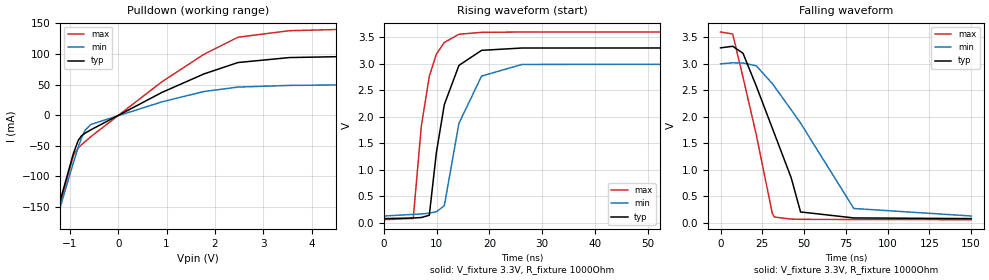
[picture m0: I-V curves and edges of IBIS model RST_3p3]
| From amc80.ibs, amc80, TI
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|   RST model
[Model]  RST_3p3
Model_type   Open_drain
Polarity   Non-Inverting
Vmeas = 1.65
Vref = 1.65
Cref = 15pF
Rref = 50
|   typ   min   max
|   (nom PVT)   (Fast PVT)   (slow PVT)
|   ON state : BUFFER OUTPUT TURNED HIGH
|C_comp   1.331E-12   1.038E-12   1.439E-12
|   OFF state: BUFFER OUTPUT TURNED LOW
C_comp   9.685E-13   8.955E-13   1.043E-12
| Where   nom PVT is  Nominal Process, 3.3V, 27C
|   Fast PVT is Strong Process, 3.6V, -40C
|   Slow PVT is Weak Process, 3.0V, 125C
|C_comp - from L-C Tank method, L = 1nH, peak frequency
[Voltage Range]   3.3   3   3.6
[Temperature Range]   27   125   -40
[Pullup Reference]   3.3   3   3.6
[Pulldown Reference]   0   0   0
[Power Clamp Reference]   3.3   3   3.6
[GND Clamp Reference]   0   0   0
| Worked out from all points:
|   slope of the pulldown table from 0 to 0.495 V, typ, clamps not added: 23.9 ohm
|   falling waveform, V_fixture 3.3V, R_fixture 1000Ohm: 20-80 % time 23ns typ, 36.1ns min, 15.5ns max; typ from 3.3 V to 0.076 V
|   rising waveform, V_fixture 3.3V, R_fixture 1000Ohm: 20-80 % time 3.39ns typ, 4.04ns min, 2.82ns max; typ from 0.076 V to 3.3 V
[Pulldown]
|   Voltage   I(typ)   I(min)   I(max)
-3.3V     -814.3mA   -776mA     -897.8mA
-1.355V   -184.2mA   -192.7mA   -192.2mA
-924.6mV  -62.57mA   -77.64mA   -65.52mA
-824.8mV  -41.33mA   -52.07mA   -53.75mA
-756.1mV  -33.8mA    -37.26mA   -48.57mA
-683.5mV  -29.6mA    -24.88mA   -43.56mA
-564.1mV  -24.16mA   -15.38mA   -35.33mA
902.3mV   36.99mA    21.58mA    54.48mA
1.771V    67.33mA    38.52mA    99.45mA
2.476V    86.03mA    45.8mA     127.5mA
3.539V    94.17mA    48.55mA    138.2mA
6.59V     98.58mA    50.8mA     144.3mA
[Ramp]
R_load = 1000
|   typ   min   max
dV/dt_r   1.93427/3.39136e-009   1.72477/4.03427e-009   2.12651/2.82941e-009
dV/dt_f   1.93427/2.30218e-008   1.72258/3.61648e-008   2.12651/1.55468e-008
[Falling Waveform]
V_fixture = 3.3V
V_fixture_min = 3V
V_fixture_max = 3.6V
R_fixture = 1000Ohm
C_fixture = 0F
|   Time   V(typ)   V(min)   V(max)
0s        3.3V       2.997V     3.6V
7.273ns   3.33V      3.018V     3.562V
13.45ns   3.198V     3.013V     2.746V
21.38ns   2.58V      2.962V     1.661V
30.94ns   1.788V     2.627V     180mV
32.2ns    1.684V     2.573V     106.3mV
42.24ns   850.7mV    2.132V     67.27mV
47.9ns    201.5mV    1.879V     62.01mV
79.76ns   89.09mV    267.1mV    60.07mV
150ns     76.22mV    125.6mV    55.81mV
[Rising Waveform]
V_fixture = 3.3V
V_fixture_min = 3V
V_fixture_max = 3.6V
R_fixture = 1000Ohm
C_fixture = 0F
|   Time   V(typ)   V(min)   V(max)
0s        76.22mV    125.4mV    55.81mV
5.534ns   87.8mV     155.7mV    80.88mV
7.069ns   96.93mV    164.1mV    1.822V
8.582ns   138.8mV    177.5mV    2.763V
9.923ns   1.322V     206mV      3.182V
11.43ns   2.228V     318.5mV    3.402V
14.2ns    2.968V     1.874V     3.557V
18.5ns    3.253V     2.767V     3.593V
26.16ns   3.297V     2.987V     3.599V
150ns     3.3V       3V         3.6V
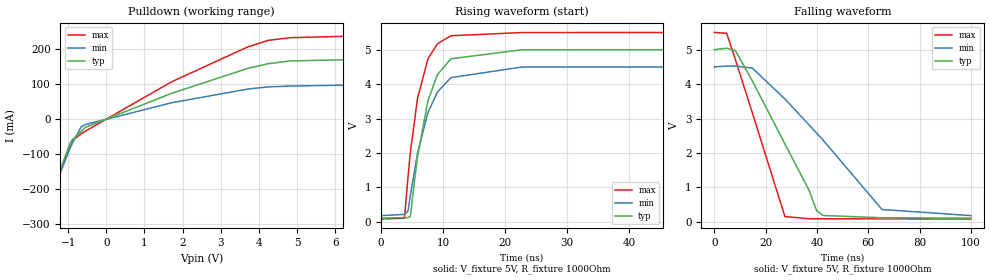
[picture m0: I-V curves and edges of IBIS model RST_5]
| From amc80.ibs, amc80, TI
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[Model]  RST_5
Model_type   Open_drain
Polarity   Non-Inverting
Vmeas = 2.5
Vref = 2.5
Cref = 15pF
Rref = 50
|   typ   min   max
|   (nom PVT)   (Fast PVT)   (slow PVT)
|   ON state : BUFFER OUTPUT TURNED HIGH
|C_comp   1.186E-12   9.865E-13   1.446E-12
|   OFF state: BUFFER OUTPUT TURNED LOW
C_comp   8.832E-13   8.711E-13   9.685E-13
| Where   nom PVT is  Nominal Process, 5.0V, 27C
|   Fast PVT is Strong Process, 5.5V, -40C
|   Slow PVT is Weak Process, 4.5V, 125C
|C_comp - from L-C Tank method, L = 1nH, peak frequency
[Voltage Range]   5   4.5   5.5
[Temperature Range]   27   125   -40
[Pullup Reference]   5   4.5   5.5
[Pulldown Reference]   0   0   0
[Power Clamp Reference]   5   4.5   5.5
[GND Clamp Reference]   0   0   0
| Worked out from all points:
|   slope of the pulldown table from 0 to 0.75 V, typ, clamps not added: 22.5 ohm
|   falling waveform, V_fixture 5V, R_fixture 1000Ohm: 20-80 % time 20.4ns typ, 32ns min, 14ns max; typ from 5 V to 0.112 V
|   rising waveform, V_fixture 5V, R_fixture 1000Ohm: 20-80 % time 3.14ns typ, 3.72ns min, 2.65ns max; typ from 0.111 V to 5 V
[Pulldown]
|   Voltage   I(typ)   I(min)   I(max)
-5V       -1.389A    -1.3A      -1.551A
-1.725V   -300.1mA   -299.8mA   -317.2mA
-961.8mV  -74.29mA   -87.83mA   -76.18mA
-896.1mV  -60.72mA   -71.82mA   -62.84mA
-655.4mV  -35.79mA   -23.02mA   -43.13mA
-548.9mV  -24.76mA   -16.66mA   -35.6mA
1.703V    72.32mA    45.56mA    105.2mA
3.713V    144.3mA    85.05mA    205.8mA
4.242V    157.5mA    91.26mA    224.3mA
4.824V    165.5mA    93.67mA    232mA
8.612V    174.5mA    99.89mA    242.7mA
9.985V    186.3mA    108.6mA    261.6mA
[Ramp]
R_load = 1000
|   typ   min   max
dV/dt_r   2.93312/3.14125e-009   2.58707/3.68027e-009   3.25004/2.65269e-009
dV/dt_f   2.9331/2.04019e-008   2.58984/3.20398e-008   3.25004/1.39605e-008
[Falling Waveform]
V_fixture = 5V
V_fixture_min = 4.5V
V_fixture_max = 5.5V
R_fixture = 1000Ohm
C_fixture = 0F
|   Time   V(typ)   V(min)   V(max)
0s        5V         4.5V       5.5V
4.832ns   5.043V     4.523V     5.476V
8.264ns   4.97V      4.526V     4.705V
14.86ns   4.09V      4.464V     3.163V
27.54ns   2.262V     3.569V     155.4mV
36.97ns   914.5mV    2.812V     93.2mV
39.85ns   330.6mV    2.582V     92.75mV
42.28ns   187.1mV    2.386V     92.37mV
65.37ns   120.7mV    360.3mV    88.73mV
100ns     111.5mV    183.6mV    83.27mV
[Rising Waveform]
V_fixture = 5V
V_fixture_min = 4.5V
V_fixture_max = 5.5V
R_fixture = 1000Ohm
C_fixture = 0F
|   Time   V(typ)   V(min)   V(max)
0s        111.5mV    183.8mV    83.27mV
3.792ns   122.8mV    218.1mV    110mV
4.363ns   124.5mV    317.8mV    1.313V
4.727ns   161.3mV    748.7mV    1.994V
5.88ns    1.874V     1.987V     3.576V
7.572ns   3.522V     3.175V     4.735V
9.111ns   4.279V     3.777V     5.175V
11.28ns   4.736V     4.189V     5.405V
22.74ns   4.998V     4.497V     5.498V
100ns     5V         4.496V     5.5V
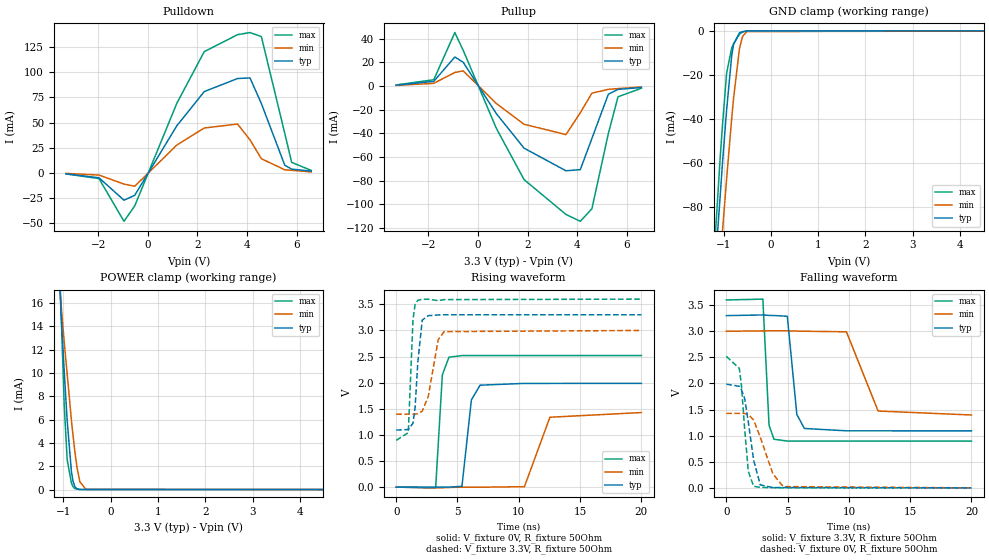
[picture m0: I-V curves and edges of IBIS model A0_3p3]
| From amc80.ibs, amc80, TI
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|   A0 model
[Model]  A0_3p3
Model_type   I/O
Polarity   Non-Inverting
Enable   Active-Low
Vinl = 0.8
Vinh = 2
Vmeas = 1.65
Vref = 1.65
Cref = 15pF
Rref = 50
|   typ   min   max
|   (nom PVT)   (Fast PVT)   (slow PVT)
|   BUFFER as INPUT
|C_comp   1.799E-12   1.507E-12   2.061E-12
|   BUFFER OUTPUT TURNED HIGH
|C_comp   1.730E-12   1.615E-12   1.787E-12
|   BUFFER OUTPUT TURNED LOW
C_comp   1.652E-12   1.439E-12   1.779E-12
| Where   nom PVT is  Nominal Process, 3.3V, 27C
|   Fast PVT is Strong Process, 3.6V, -40C
|   Slow PVT is Weak Process, 3.0V, 125C
|C_comp - from L-C Tank method, L = 1nH, peak frequency
[Voltage Range]   3.3   3   3.6
[Temperature Range]   27   125   -40
[Pullup Reference]   3.3   3   3.6
[Pulldown Reference]   0   0   0
[Power Clamp Reference]   3.3   3   3.6
[GND Clamp Reference]   0   0   0
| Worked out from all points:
|   slope of the pulldown table from 0 to 0.495 V, typ, clamps not added: 23.8 ohm
|   slope of the pullup table from 0 to 0.495 V, typ, clamps not added: 30.7 ohm
|   GND clamp passes 1 mA (typ) near -0.67 V on its own axis
|   POWER clamp passes 1 mA (typ) near -0.81 V on its own axis
|   falling waveform, V_fixture 3.3V, R_fixture 50Ohm: 20-80 % time 488ps typ, 1.12ns min, 294ps max; typ from 3.3 V to 1.09 V
|   rising waveform, V_fixture 0V, R_fixture 50Ohm: 20-80 % time 475ps typ, 958ps min, 306ps max; typ from 0 V to 1.99 V
|   rising waveform, V_fixture 3.3V, R_fixture 50Ohm: 20-80 % time 349ps typ, 693ps min, 243ps max; typ from 1.09 V to 3.3 V
|   falling waveform, V_fixture 0V, R_fixture 50Ohm: 20-80 % time 735ps typ, 1.23ns min, 496ps max; typ from 1.99 V to 0 V
[Pulldown]
|   Voltage   I(typ)   I(min)   I(max)
-3.3V     -1.175mA   -709.3uA   -1.236mA
-1.972V   -5.093mA   -2.383mA   -5.88mA
-963.1mV  -27.42mA   -11.33mA   -48.43mA
-529.5mV  -22.47mA   -13.5mA    -33.01mA
1.168V    46.74mA    27.55mA    69.14mA
2.274V    80.8mA     44.52mA    120.6mA
3.617V    93.81mA    48.47mA    137.5mA
4.119V    94.43mA    32.76mA    139.6mA
4.578V    68.89mA    13.93mA    135.6mA
5.521V    7.533mA    2.891mA    39.29mA
5.8V      3.545mA    2.339mA    10.26mA
6.59V     1.583mA    773.1uA    2.292mA
[GND Clamp]
|   Voltage   I(typ)   I(min)   I(max)
-3.3V     -808.9mA   -769.8mA   -893.6mA
-1.223V   -121.5mA   -147.5mA   -109.9mA
-1.171V   -104.9mA   -132.4mA   -91.88mA
-1.071V   -74.76mA   -104.1mA   -57.53mA
-1.016V   -58.11mA   -89.07mA   -41.04mA
-934.7mV  -35.86mA   -67.02mA   -19.19mA
-827.5mV  -11.31mA   -39.73mA   -7.752mA
-787mV    -6.029mA   -30.41mA   -5.902mA
-662.1mV  -884uA     -7.82mA    -1.506mA
-597.2mV  -409.2uA   -2.526mA   -463.9uA
-507.2mV  -88.16uA   -343.9uA   -46.63uA
6.59V     0A         0A         0A
[Pullup]
|   Voltage   I(typ)   I(min)   I(max)
-3.3V     838.5uA    589uA      957.1uA
-1.785V   3.995mA    2.329mA    5.396mA
-934.7mV  24.58mA    11.54mA    45.22mA
-597.2mV  20.15mA    12.87mA    30.21mA
743mV     -23.36mA   -14.78mA   -35.82mA
1.857V    -52.4mA    -32.24mA   -78.95mA
3.547V    -71.52mA   -40.97mA   -108.4mA
4.127V    -70.56mA   -22.5mA    -114.2mA
4.595V    -44.2mA    -5.965mA   -103.6mA
5.259V    -6.805mA   -2.724mA   -39.96mA
5.649V    -2.762mA   -2.117mA   -8.998mA
6.59V     -1.19mA    -650.2uA   -1.826mA
[POWER Clamp]
|   Voltage   I(typ)   I(min)   I(max)
-3.3V     261.6mA    182.4mA    376.9mA
-1.077V   17.83mA    17.41mA    19mA
-1.04V    14.51mA    15.55mA    14.53mA
-980.9mV  10.21mA    12.68mA    7.284mA
-917.7mV  5.906mA    9.9mA      2.557mA
-827.5mV  1.525mA    5.931mA    553.1uA
-794.7mV  720.3uA    4.675mA    256.2uA
-754.5mV  244.2uA    3.248mA    80.4uA
-709.6mV  76.81uA    1.892mA    48.28uA
-648.9mV  11.09uA    666.7uA    4.808uA
-522mV    8.862uA    26.29uA    2.204uA
6.59V     0A         0A         0A
[Ramp]
R_load = 50
|   typ   min   max
dV/dt_r   1.19193/4.69354e-010   0.85652/9.52893e-010   1.51191/3.05784e-010
dV/dt_f   1.32484/4.84931e-010  0.962182/1.11589e-009   1.62278/2.91861e-010
[Falling Waveform]
V_fixture = 3.3V
V_fixture_min = 3V
V_fixture_max = 3.6V
R_fixture = 50Ohm
C_fixture = 0F
|   Time   V(typ)   V(min)   V(max)
0s        3.3V       3V         3.6V
2.979ns   3.313V     3.008V     3.616V
3.485ns   3.304V     3.009V     1.2V
3.888ns   3.302V     3.01V      931.2mV
4.974ns   3.288V     3.009V     897.2mV
5.752ns   1.407V     3.004V     896mV
6.365ns   1.138V     3.001V     896mV
9.798ns   1.093V     2.99V      895.8mV
12.38ns   1.093V     1.472V     895.7mV
20ns      1.092V     1.396V     895.4mV
[Rising Waveform]
V_fixture = 0V
V_fixture_min = 0V
V_fixture_max = 0V
R_fixture = 50Ohm
C_fixture = 0F
|   Time   V(typ)   V(min)   V(max)
0s        344.5nV    875.3nV    199.8nV
3.219ns   -586.7uV   -14.33mV   -13.52mV
3.764ns   -283.9uV   -12.17mV   2.15V
4.305ns   17.03uV    -6.27mV    2.488V
5.364ns   15.35mV    -937.8uV   2.519V
6.134ns   1.671V     -1.568mV   2.519V
6.842ns   1.952V     -2.148mV   2.519V
10.46ns   1.986V     8.086mV    2.519V
12.54ns   1.986V     1.338V     2.52V
20ns      1.987V     1.428V     2.52V
[Rising Waveform]
V_fixture = 3.3V
V_fixture_min = 3V
V_fixture_max = 3.6V
R_fixture = 50Ohm
C_fixture = 0F
|   Time   V(typ)   V(min)   V(max)
0s        1.092V     1.396V     895.4mV
984.8ps   1.102V     1.398V     1.043V
1.373ns   1.226V     1.399V     3.22V
1.541ns   1.525V     1.399V     3.496V
1.761ns   2.386V     1.405V     3.578V
2.123ns   3.199V     1.454V     3.596V
2.618ns   3.283V     1.738V     3.599V
3.424ns   3.297V     2.818V     3.571V
3.906ns   3.3V       2.978V     3.591V
20ns      3.3V       3V         3.6V
[Falling Waveform]
|Gnd
V_fixture = 0V
V_fixture_min = 0V
V_fixture_max = 0V
R_fixture = 50Ohm
C_fixture = 0F
|   Time   V(typ)   V(min)   V(max)
0s        1.987V     1.428V     2.52V
1.06ns    1.946V     1.427V     2.288V
1.228ns   1.885V     1.427V     1.975V
1.498ns   1.708V     1.426V     1.12V
1.793ns   1.261V     1.406V     316.1mV
2.23ns    529.1mV    1.299V     28.41mV
2.77ns    56.42mV    968.2mV    10.17mV
3.796ns   4.617mV    269.2mV    3.856mV
4.634ns   6.957mV    24.82mV    485.3uV
20ns      344.5nV    874.9nV    199.9nV
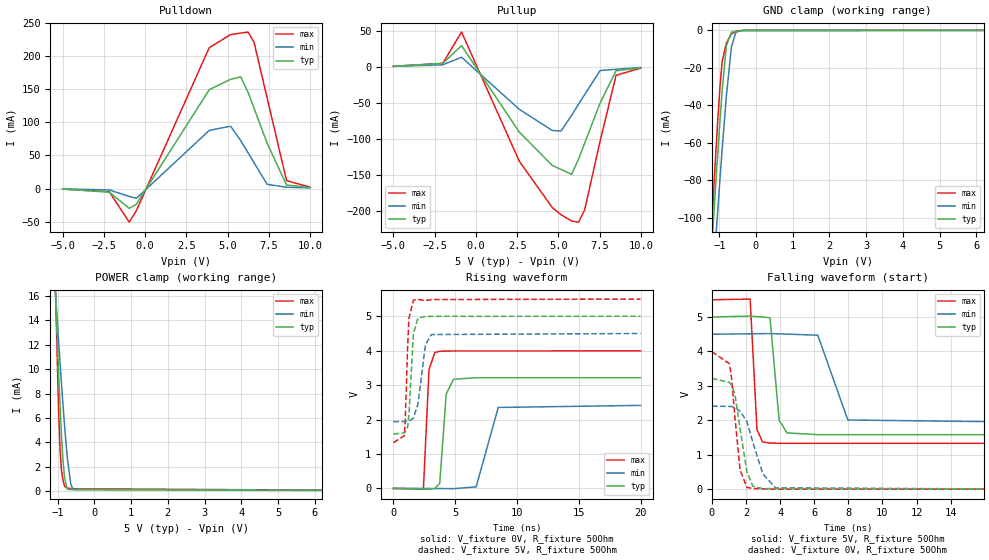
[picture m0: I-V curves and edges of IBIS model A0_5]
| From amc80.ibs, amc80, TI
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[Model]  A0_5
Model_type   I/O
Polarity   Non-Inverting
Enable   Active-Low
Vinl = 0.8
Vinh = 2
Vmeas = 2.5
Vref = 2.5
Cref = 15pF
Rref = 50
|   typ   min   max
|   (nom PVT)   (Fast PVT)   (slow PVT)
|   BUFFER as INPUT
|C_comp   1.730E-12   1.432E-12   1.862E-12
|   BUFFER OUTPUT TURNED HIGH
|C_comp   1.466E-12   1.459E-12   1.614E-12
|   BUFFER OUTPUT TURNED LOW
C_comp   1.486E-12   1.374E-12   1.652E-12
| Where   nom PVT is  Nominal Process, 5.0V, 27C
|   Fast PVT is Strong Process, 5.5V, -40C
|   Slow PVT is Weak Process, 4.5V, 125C
|C_comp - from L-C Tank method, L = 1nH, peak frequency
[Voltage Range]   5   4.5   5.5
[Temperature Range]   27   125   -40
[Pullup Reference]   5   4.5   5.5
[Pulldown Reference]   0   0   0
[Power Clamp Reference]   5   4.5   5.5
[GND Clamp Reference]   0   0   0
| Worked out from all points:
|   slope of the pulldown table from 0 to 0.75 V, typ, clamps not added: 22.6 ohm
|   slope of the pullup table from 0 to 0.75 V, typ, clamps not added: 26.9 ohm
|   GND clamp passes 1 mA (typ) near -0.67 V on its own axis
|   POWER clamp passes 1 mA (typ) near -0.81 V on its own axis
|   falling waveform, V_fixture 5V, R_fixture 50Ohm: 20-80 % time 325ps typ, 640ps min, 226ps max; typ from 5 V to 1.58 V
|   rising waveform, V_fixture 0V, R_fixture 50Ohm: 20-80 % time 345ps typ, 610ps min, 250ps max; typ from 0 V to 3.22 V
|   rising waveform, V_fixture 5V, R_fixture 50Ohm: 20-80 % time 302ps typ, 517ps min, 238ps max; typ from 1.58 V to 5 V
|   falling waveform, V_fixture 0V, R_fixture 50Ohm: 20-80 % time 574ps typ, 876ps min, 430ps max; typ from 3.22 V to 0 V
[Pulldown]
|   Voltage   I(typ)   I(min)   I(max)
-5V       -736.2uA   -519.2uA   -724.3uA
-2.168V   -5.525mA   -2.14mA    -4.899mA
-962.6mV  -29.96mA   -11.89mA   -50.83mA
-530.9mV  -23.62mA   -14.8mA    -33.6mA
3.89V     149.3mA    87.81mA    212.8mA
5.183V    165mA      94.18mA    232.5mA
5.803V    168.6mA    72.24mA    234.8mA
6.248V    145.1mA    53.83mA    236.3mA
6.607V    121.3mA    39.03mA    220.9mA
7.399V    68.57mA    6.298mA    136.9mA
8.578V    5.282mA    2.007mA    11.93mA
9.985V    1.703mA    965.1uA    2.2mA
[GND Clamp]
|   Voltage   I(typ)   I(min)   I(max)
-5V       -1.381A    -1.29A     -1.545A
-1.241V   -127.1mA   -152.1mA   -116.4mA
-1.137V   -94.9mA    -123.2mA   -79.87mA
-1.078V   -76.44mA   -106.5mA   -60.04mA
-1.048V   -67.82mA   -98.25mA   -50.14mA
-980.7mV  -48.24mA   -79.41mA   -30.14mA
-919.9mV  -31.94mA   -63.22mA   -16.41mA
-807mV    -8.294mA   -35.16mA   -6.834mA
-669.1mV  -994uA     -8.907mA   -1.932mA
-545.5mV  -705.3uA   -853.3uA   -451.4uA
-347.5mV  -243.1uA   -4.497uA   -2.357uA
9.985V    0A         0A         0A
[Pullup]
|   Voltage   I(typ)   I(min)   I(max)
-5V       581.8uA    454.9uA    619.1uA
-2.011V   4.527mA    2.646mA    4.591mA
-871.6mV  29.21mA    13.18mA    48.03mA
2.633V    -90.79mA   -59.17mA   -131.2mA
4.633V    -137mA     -88.46mA   -195.5mA
5.163V    -142.6mA   -89.26mA   -205.4mA
5.803V    -149.4mA   -67.45mA   -214.1mA
6.222V    -128.2mA   -52.09mA   -215.7mA
6.597V    -105.9mA   -38.63mA   -198.4mA
7.532V    -50.27mA   -5.259mA   -103.2mA
8.499V    -5.545mA   -3.593mA   -11.86mA
9.985V    -1.656mA   -1.033mA   -2.065mA
[POWER Clamp]
|   Voltage   I(typ)   I(min)   I(max)
-5V       454mA      315.5mA    657.3mA
-1.073V   17.48mA    17.05mA    18.43mA
-1.06V    16.37mA    16.42mA    16.68mA
-971.8mV  9.471mA    12.23mA    6.393mA
-930.2mV  6.767mA    10.35mA    3.206mA
-895.4mV  4.52mA     8.844mA    1.707mA
-854.1mV  2.505mA    7.055mA    876uA
-807mV    970uA      5.168mA    374.3uA
-734.9mV  138.3uA    2.688mA    227.1uA
-641.5mV  112uA      570.9uA    197.3uA
-582.8mV  95.49uA    137.3uA    178.6uA
9.985V    0A         0A         0A
[Ramp]
R_load = 50
|   typ   min   max
dV/dt_r   1.92936/3.43663e-010   1.44734/6.03922e-010   2.39556/2.48588e-010
dV/dt_f   2.05119/3.22273e-010   1.53749/6.3371e-010   2.50192/2.25003e-010
[Falling Waveform]
V_fixture = 5V
V_fixture_min = 4.5V
V_fixture_max = 5.5V
R_fixture = 50Ohm
C_fixture = 0F
|   Time   V(typ)   V(min)   V(max)
0s        5V         4.5V       5.5V
2.242ns   5.027V     4.512V     5.521V
2.643ns   5.01V      4.514V     1.733V
2.963ns   5.004V     4.516V     1.375V
3.406ns   4.976V     4.519V     1.34V
3.943ns   2.002V     4.51V      1.332V
4.407ns   1.634V     4.503V     1.331V
6.21ns    1.583V     4.471V     1.331V
7.971ns   1.582V     2.009V     1.331V
20ns      1.581V     1.938V     1.33V
[Rising Waveform]
V_fixture = 0V
V_fixture_min = 0V
V_fixture_max = 0V
R_fixture = 50Ohm
C_fixture = 0F
|   Time   V(typ)   V(min)   V(max)
0s        329.3nV    663.4nV    197.7nV
2.426ns   -1.697mV   -21.39mV   -9.064mV
2.878ns   -584.1uV   -16.15mV   3.449V
3.344ns   -5.055mV   -4.723mV   3.947V
3.746ns   148.6mV    -2.821mV   3.983V
4.271ns   2.745V     -4.747mV   3.991V
4.861ns   3.169V     -6.908mV   3.992V
6.692ns   3.215V     45.38mV    3.992V
8.481ns   3.215V     2.352V     3.992V
20ns      3.216V     2.412V     3.993V
[Rising Waveform]
V_fixture = 5V
V_fixture_min = 4.5V
V_fixture_max = 5.5V
R_fixture = 50Ohm
C_fixture = 0F
|   Time   V(typ)   V(min)   V(max)
0s        1.581V     1.938V     1.33V
881ps     1.612V     1.947V     1.533V
954.5ps   1.639V     1.947V     1.973V
1.149ns   1.787V     1.949V     4.134V
1.251ns   2.127V     1.95V      4.935V
1.613ns   4.477V     2.039V     5.469V
1.984ns   4.95V      2.451V     5.49V
2.594ns   4.995V     4.181V     5.457V
3.075ns   4.999V     4.47V      5.486V
20ns      5V         4.5V       5.5V
[Falling Waveform]
|Gnd
V_fixture = 0V
V_fixture_min = 0V
V_fixture_max = 0V
R_fixture = 50Ohm
C_fixture = 0F
|   Time   V(typ)   V(min)   V(max)
0s        3.216V     2.412V     3.993V
1.027ns   3.1V       2.402V     3.646V
1.158ns   3.012V     2.401V     3.212V
1.343ns   2.775V     2.37V      2.128V
1.65ns    1.762V     2.267V     565.8mV
2.053ns   503.3mV    1.963V     48.75mV
2.4ns     89.2mV     1.361V     21.97mV
2.986ns   12.34mV    443.8mV    6.692mV
3.729ns   21.69mV    36.2mV     709.7uV
20ns      329.4nV    663.5nV    197.8nV
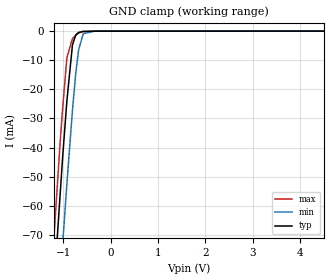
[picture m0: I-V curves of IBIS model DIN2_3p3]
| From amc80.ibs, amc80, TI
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|   DIN2 model
[Model]  DIN2_3p3
Model_type   Input
Vinl = 0.8
Vinh = 2.0
|   typ   min   max
|   (nom PVT)   (Fast PVT)   (slow PVT)
C_comp   5.835E-13   5.676E-13   6.224E-13
| Where   nom PVT is  Nominal Process, 3.3V, 27C
|   Fast PVT is Strong Process, 3.6V, -40C
|   Slow PVT is Weak Process, 3.0V, 125C
|C_comp - from L-C Tank method, L = 1nH, peak frequency
| Where   nom PVT is  Nominal Process, 3.3V, 27C
|   Fast PVT is Strong Process, 3.6V, -40C
|   Slow PVT is Weak Process, 3.0V, 125C
|C_comp - from L-C Tank method, L = 1nH, peak frequency
[Voltage Range]   3.3   3   3.6
[Temperature Range]   27   125   -40
[Power Clamp Reference]   3.3   3   3.6
[GND Clamp Reference]   0   0   0
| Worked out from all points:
|   GND clamp passes 1 mA (typ) near -0.72 V on its own axis
[GND Clamp]
|   Voltage   I(typ)   I(min)   I(max)
-3.3V     -646.6mA   -664.3mA   -639.2mA
-1.233V   -97.24mA   -127mA     -79.71mA
-1.171V   -81.48mA   -111.4mA   -64.21mA
-1.064V   -55.52mA   -85.13mA   -37.57mA
-1.014V   -43.35mA   -73.27mA   -26.64mA
-924.4mV  -23.98mA   -52.53mA   -9.169mA
-806.3mV  -4.748mA   -27.19mA   -2.534mA
-736.8mV  -1.299mA   -14.5mA    -1.496mA
-675.7mV  -477.6uA   -6.375mA   -602.2uA
-578.1mV  -79.57uA   -895.2uA   -247.7uA
-330.4mV  -33.16uA   -1.944uA   -7.412uA
6.59V     0A         0A         0A
[POWER Clamp]
|   SCR cell for ESD function. Effects occurr above VDD x 2
|   Voltage   I(typ)   I(min)   I(max)
-3.3V     0A         0A         0A
0V        0A         0A         0A
6.6V      0A         0A         0A
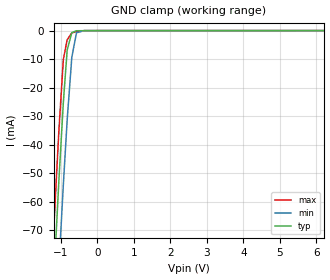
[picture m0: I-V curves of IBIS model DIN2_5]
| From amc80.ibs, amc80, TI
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[Model]  DIN2_5
Model_type   Input
Vinl = 0.8
Vinh = 2.0
|   typ   min   max
|   (nom PVT)   (Fast PVT)   (slow PVT)
C_comp   5.599E-13   5.249E-13   5.755E-13
| Where   nom PVT is  Nominal Process, 5.0V, 27C
|   Fast PVT is Strong Process, 5.5V, -40C
|   Slow PVT is Weak Process, 4.5V, 125C
|C_comp - from L-C Tank method, L = 1nH, peak frequency
[Voltage Range]   5   4.5   5.5
[Temperature Range]   27   125   -40
[Power Clamp Reference]   5   4.5   5.5
[GND Clamp Reference]   0   0   0
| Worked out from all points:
|   GND clamp passes 1 mA (typ) near -0.72 V on its own axis
[GND Clamp]
|   Voltage   I(typ)   I(min)   I(max)
-5V       -1.106A    -1.116A    -1.106A
-1.657V   -207mA     -234mA     -191.7mA
-1.246V   -100.3mA   -129.5mA   -83.05mA
-1.232V   -96.9mA    -126.2mA   -79.47mA
-1.127V   -70.99mA   -100.9mA   -52.97mA
-1.053V   -52.57mA   -82.89mA   -35.09mA
-930.8mV  -25.13mA   -53.93mA   -10.09mA
-826.6mV  -6.886mA   -31.41mA   -3.251mA
-699.6mV  -709.6uA   -9.376mA   -833.7uA
-570.9mV  -61.44uA   -767.5uA   -355.1uA
-355.4mV  -35.68uA   -3.928uA   -2.9uA
9.985V    0A         0A         0A
[POWER Clamp]
|   SCR cell for ESD function. Effects occurr above VDD x 2
|   Voltage   I(typ)   I(min)   I(max)
-5V       0A         0A         0A
0V        0A         0A         0A
10V       0A         0A         0A
